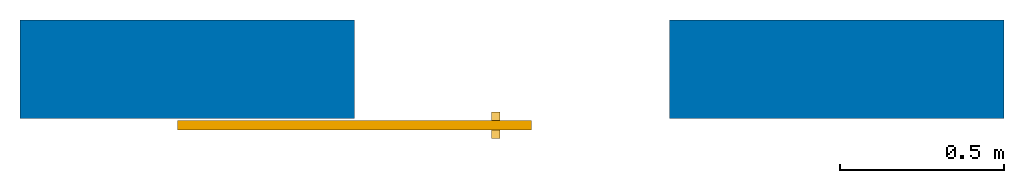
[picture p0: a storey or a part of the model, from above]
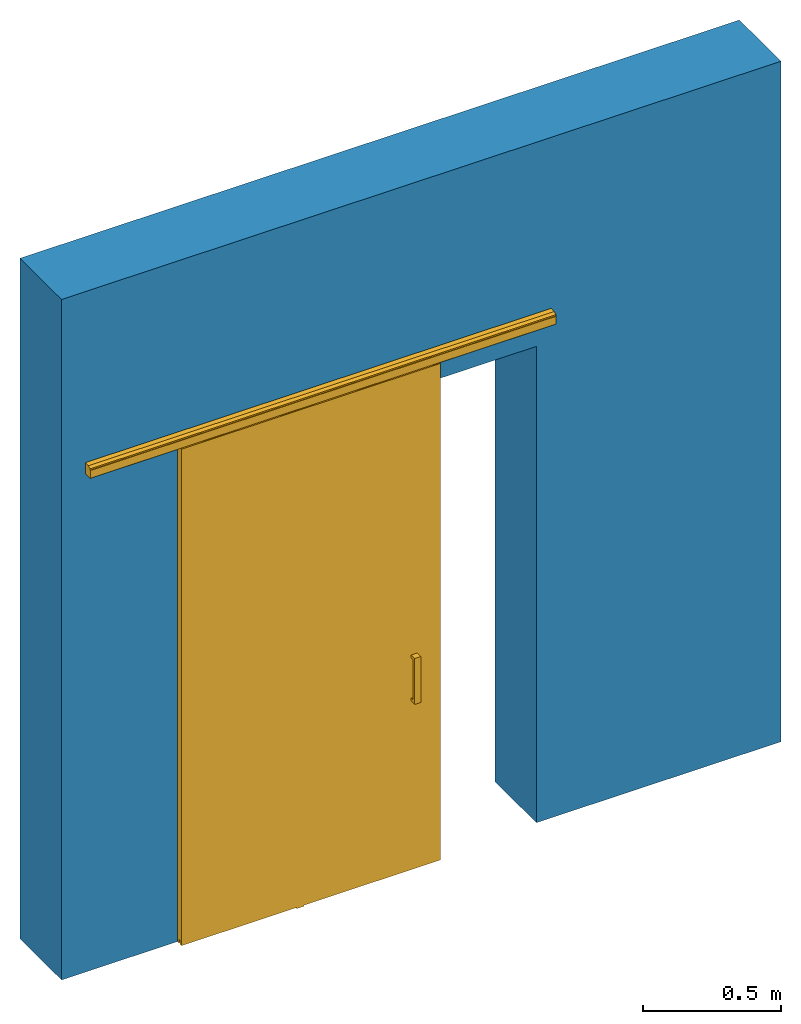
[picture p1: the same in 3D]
Properties of the parts of a building model (IFC2X3)

# File
Description: ViewDefinition [CoordinationView_V2.0]
File name: Número de proyecto
Time: 2017-11-13T15:21:51
Written by: The EXPRESS Data Manager Version 5.02.0100.07 : 28 Aug 2013
Made in: 20160512_1515(x64) - Exporter 15.6.0.0 - Alternate UI 15.6.0.0
Comment: STEP Physical File produced by: The EXPRESS Data Manager Version 5.02.0100.07 : 28 Aug 2013 * Module: EDMstepFileFactory/EDMstandAlone * Creation date: Mon Nov 13 15:21:51 2017 * Host: MSI * Database: C:\Users\TUMADR~1\AppData\Local\Temp\{360D109C-51FD-4CA9-BB57-8D386338EC4B}\ifc * Database version: 5507 * Database creation date: Mon Nov 13 15:21:49 2017 * Schema: IFC2X3 * Model: DataRepository.ifc * Model creation date: Mon Nov 13 15:21:49 2017 * Header model: DataRepository.ifc_HeaderModel * Header model creation date: Mon Nov 13 15:21:49 2017 * EDMuser: sdai-user * EDMgroup: sdai-group * License ID and type: 5605 : Permanent license. Expiry date: * EDMstepFileFactory options: 020000

# IfcProject, Número de proyecto
LongName: Nombre de proyecto; Phase: Estado de proyecto

# IfcSite, Default
RefLatitude: 40, 25, 0, 86975; RefLongitude: -3, -42, -1, -243858; RefElevation: 0 m
Other - Category: Project Information; Client Name: Propietario; Project Address: Introduzca dirección aquí; Project Issue Date: Fecha de emisión; Project Name: Nombre de proyecto; Project Number: Número de proyecto; Project Status: Estado de proyecto

# IfcBuilding
Pset_BuildingCommon - NumberOfStoreys: 1
Other - Category: Project Information; Client Name: Propietario; Project Address: Introduzca dirección aquí; Project Issue Date: Fecha de emisión; Project Name: Nombre de proyecto; Project Number: Número de proyecto; Project Status: Estado de proyecto

# IfcBuildingStorey, Nivel 1
LongName: Nivel 1; Elevation: 0 m
Constraints - Elevation: 0 m; Elevation Base: Project Base Point
Dimensions - Computation Height: 0 m
Identity Data - Structural: no; Building Story: yes; Name: Nivel 1; Type Name: Nivel 1
Other - Category: Levels; Family: Level: Nivel 1; Family and Type: Level: Nivel 1; Type: Level: Nivel 1; Type Id: Level: Nivel 1; Family Name: Level
Graphics - Color: 0; Line Pattern: Trazo punto; Line Weight: 1; Symbol: Extremo de nivel: Extremo de nivel; Symbol at End 1 Default: no; Symbol at End 2 Default: yes

# IfcDoor: Default, EU-2015_Door_Klein_Lite+100-KSC:Default:152321
In: Nivel 1
Type - ParameterTakesPrecedence: no; Sizeable: no; Material: Aluminium, Anodized Silver, Acetal Resin-Black, Acetal Resin-White, Birch, Natural
Type - Analysis Results - SurfaceMass: 0
Type - Analytical Properties - Analytic Construction: <None>
Type - Construction - IsExternal: no; HandicapAccessible: no; FireExit: no; SmokeStop: no; Function: Interior; HasDrive: no; Wall Closure: By host
Type - Data - GlazingAreaFraction: 0
Type - Dimensions - Handle Height: 0.85 m; Height: 2.1 m; Rough Height: 0 m; Rough Width: 1.07 m; Thickness: 0.03 m; True Thickness: 0.03 m; Width: 0.8 m
Type - General - IFCClassification: IfcDoor; MasterformatCode: 08 12 16; MasterformatTitle: Aluminum Frames; OmniclassCode: 23-17 11 23 13; OmniclassTitle: Sliding All Glass Doors; Uniclass2.0Code: 30-59-23-02; Uniclass2.0Title: Aluminium door frames; UNSPSCCode: 30162306; UNSPSCTitle: Door mount or sliding towel hardware or assembly
Type - Green Building Properties - EmbodiedCarbon: 0; EnergeticCostKw·h: 0; EnergeticCostMJ: 0; RawMaterial: 0
Type - Identity Data - Author: Bimetica Parametric Design Services S.L.; BIMElementExpiryDate: 13/11/2018; BIMElementIssueDate: 13/11/2017; BIMElementVersion: V01; Bimetica: www.bimetica.com; ContactEmail: bim@klein.es; ContactReference: Technical Department; ContactTelephone: (+34) 935 760 101; Description: Sliding Glass Door; Manufacturer: Klein; Model: Lite+; OmniClass Number: 23.30.10.17.11; OmniClass Title: Sliding Doors; ProductURL: http://www.klein-europe.com/en/sliding-doors/lite; Reference: LITE+ 100 KSC Retrac; TechnicalInformation: http://www.klein-europe.com/en/sliding-doors/lite; Type Comments: Door maximum weight up to 100Kg. All dimensions must be checked with KLEIN mounting instructions. The system is available in Silver, Black or Dark Bronze anodized finish. KSC optional (Klein Soft Closing) for a smooth and controlled closing for glass width starting at 750mm. Check the feasibility of the system on our Website.; Type Mark: 5; Type Name: Default; URL: http://www.klein-europe.com/en/
Type - Materials and Finishes - End Caps: Acetal Resin-White; Frame Material: Aluminium, Anodized Silver; Panel Material: Birch, Natural
Type - Other - Category: Doors; Family Name: EU-2015_Door_Klein_Lite+100-KSC; MaintenanceCost: 0
OverallHeight: 2.1 m; OverallWidth: 0.96 m
Pset_DoorCommon - Reference: LITE+ 100 KSC Retrac; IsExternal: no; HandicapAccessible: no; FireExit: no; SmokeStop: no; GlazingAreaFraction: 0
Pset_ManufacturerTypeInformation - Manufacturer: Klein
Constraints - Ceiling Mounted: no; Central Door: yes; Door Against Wall: no; Level: Level: Nivel 1; Recessed Installation: no; Sill Height: 0 m; Wall Mounted - 17mm: no; Wall Mounted - 6mm: yes
Construction - Handle Type: U Handle
Dimensions - A: 0.1 m; Aperture Length: 0.48 m; Area: 2.63293 m2; ExteriorOffset: 0 m; Gap: 0.16 m; Guide Stop: 0.06 m; Handle Distance from Wall: 0.11 m; InteriorOffset: 0 m; Panel Width: 1.08 m; Perimeter: 6560; Real Ext Offset: 0 m; Real Int Offset: 0.021 m; Real Opening: 0.96 m; Recessed Height: 0 m; Track Length: 1.88 m; True Opening: 0.48 m; Volume: 0.0724781 m3; Wall Mountred Distance: 0.021 m
Division Geometry - Aperture: 0.5
Identity Data - Mark: 1
Other - Family: EU-2015_Door_Klein_Lite+100-KSC: Default; Family and Type: EU-2015_Door_Klein_Lite+100-KSC: Default; Head Height: 2.1 m; Host Id: Basic Wall: Por defecto - 30 cm; Type: EU-2015_Door_Klein_Lite+100-KSC: Default; Type Id: EU-2015_Door_Klein_Lite+100-KSC: Default; Wall Mounted: yes
Phasing - Phase Created: Nueva construcción

# IfcWallStandardCase: Basic Wall:Por defecto - 30 cm, Basic Wall:Por defecto - 30 cm:150189
In: Nivel 1
Type - PredefinedType: STANDARD; Material: Muro por defecto 0.3 m
Type - Analytical Properties - Absorptance: 0.7; Roughness: 3
Type - Construction - Function: Exterior; Width: 0.3 m; Wrapping at Inserts: Do not wrap
Type - Graphics - Coarse Scale Fill Color: 0
Type - Identity Data - Keynote: Md.1; Type Name: Por defecto - 30 cm
Type - Other - Category: Walls; Family Name: Basic Wall
Constraints - Base Constraint: Level: Nivel 1; Base Extension Distance: 0 m; Base is Attached: no; Base Offset: 0 m; Location Line: Core Face: Exterior; Related to Mass: no; Room Bounding: yes; Top Constraint: Level: Nivel 2; Top Extension Distance: 0 m; Top is Attached: no; Top Offset: 0 m; Unconnected Height: 3 m
Dimensions - Area: 6.984 m2; Length: 3 m; Volume: 2.0952 m3
Other - Family: Basic Wall: Por defecto - 30 cm; Family and Type: Basic Wall: Por defecto - 30 cm; Type: Basic Wall: Por defecto - 30 cm; Type Id: Basic Wall: Por defecto - 30 cm
Phasing - Phase Created: Nueva construcción
Structural - Enable Analytical Model: no; Structural: no; Structural Usage: Non-bearing
Pset_WallCommon - Reference: Basic Wall:Por defecto - 30 cm; LoadBearing: no; ExtendToStructure: no; IsExternal: yes
